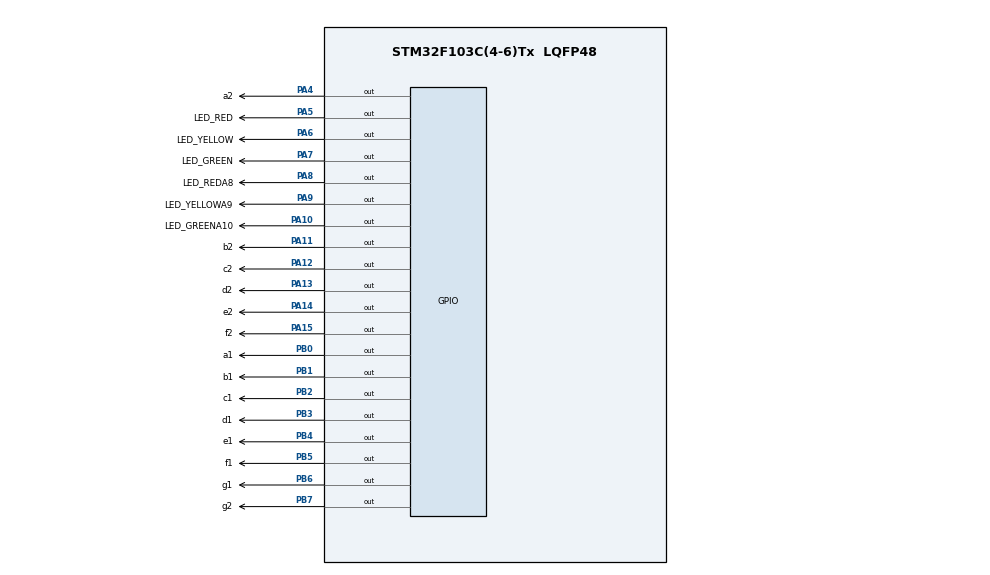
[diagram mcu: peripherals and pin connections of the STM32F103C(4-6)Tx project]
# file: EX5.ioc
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Mcu.Family=STM32F1
Mcu.Name=STM32F103C(4-6)Tx
Mcu.Package=LQFP48
NVIC.PriorityGroup=NVIC_PRIORITYGROUP_4
PA10.GPIO_Label=LED_GREENA10
PA10.Signal=GPIO_Output
PA11.GPIO_Label=b2
PA11.Signal=GPIO_Output
PA12.GPIO_Label=c2
PA12.Signal=GPIO_Output
PA13.GPIO_Label=d2
PA13.Signal=GPIO_Output
PA14.GPIO_Label=e2
PA14.Signal=GPIO_Output
PA15.GPIO_Label=f2
PA15.Signal=GPIO_Output
PA4.GPIO_Label=a2
PA4.Signal=GPIO_Output
PA5.GPIO_Label=LED_RED
PA5.Signal=GPIO_Output
PA6.GPIO_Label=LED_YELLOW
PA6.Signal=GPIO_Output
PA7.GPIO_Label=LED_GREEN
PA7.Signal=GPIO_Output
PA8.GPIO_Label=LED_REDA8
PA8.Signal=GPIO_Output
PA9.GPIO_Label=LED_YELLOWA9
PA9.Signal=GPIO_Output
PB0.GPIO_Label=a1
PB0.Signal=GPIO_Output
PB1.GPIO_Label=b1
PB1.Signal=GPIO_Output
PB2.GPIO_Label=c1
PB2.Signal=GPIO_Output
PB3.GPIO_Label=d1
PB3.Signal=GPIO_Output
PB4.GPIO_Label=e1
PB4.Signal=GPIO_Output
PB5.GPIO_Label=f1
PB5.Signal=GPIO_Output
PB6.GPIO_Label=g1
PB6.Signal=GPIO_Output
PB7.GPIO_Label=g2
PB7.Signal=GPIO_Output
ProjectManager.HeapSize=0x200
ProjectManager.StackSize=0x400
ProjectManager.TargetToolchain=STM32CubeIDE
RCC.APB1Freq_Value=8000000
RCC.APB2Freq_Value=8000000
VP_SYS_VS_ND.Mode=No_Debug
board=custom

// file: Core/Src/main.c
/* USER CODE BEGIN Header */
/**
  ******************************************************************************
  * @file           : main.c
  * @brief          : Main program body
  ******************************************************************************
  * @attention
  *
  * <h2><center>&copy; Copyright (c) 2022 STMicroelectronics.
  * All rights reserved.</center></h2>
  *
  * This software component is licensed by ST under BSD 3-Clause license,
  * the "License"; You may not use this file except in compliance with the
  * License. You may obtain a copy of the License at:
  *                        opensource.org/licenses/BSD-3-Clause
  *
  ******************************************************************************
  */
/* USER CODE END Header */
#include "main.h"

void SystemClock_Config(void);
static void MX_GPIO_Init(void);

/* USER CODE BEGIN 0 */
void clearAllClock();
void setNumberOnClock(int num);
void clearNumberOnClock(int num);

void clearAllClock()
{
	HAL_GPIO_WritePin(GPIOA, led0_Pin, GPIO_PIN_RESET);
	HAL_GPIO_WritePin(GPIOA, led1_Pin, GPIO_PIN_RESET);
	HAL_GPIO_WritePin(GPIOA, led2_Pin, GPIO_PIN_RESET);
	HAL_GPIO_WritePin(GPIOA, led3_Pin, GPIO_PIN_RESET);
	HAL_GPIO_WritePin(GPIOA, led4_Pin, GPIO_PIN_RESET);
	HAL_GPIO_WritePin(GPIOA, led5_Pin, GPIO_PIN_RESET);
	HAL_GPIO_WritePin(GPIOA, led6_Pin, GPIO_PIN_RESET);
	HAL_GPIO_WritePin(GPIOA, led7_Pin, GPIO_PIN_RESET);
	HAL_GPIO_WritePin(GPIOA, led8_Pin, GPIO_PIN_RESET);
	HAL_GPIO_WritePin(GPIOA, led9_Pin, GPIO_PIN_RESET);
	HAL_GPIO_WritePin(GPIOA, led10_Pin, GPIO_PIN_RESET);
	HAL_GPIO_WritePin(GPIOA, led11_Pin, GPIO_PIN_RESET);
}

void setNumberOnClock(int num)
{
	if(num == 0) HAL_GPIO_WritePin(led0_GPIO_Port, led0_Pin, GPIO_PIN_SET);
	if(num == 1) HAL_GPIO_WritePin(led1_GPIO_Port, led1_Pin, GPIO_PIN_SET);
	if(num == 2) HAL_GPIO_WritePin(led2_GPIO_Port, led2_Pin, GPIO_PIN_SET);
	if(num == 3) HAL_GPIO_WritePin(led3_GPIO_Port, led3_Pin, GPIO_PIN_SET);
	if(num == 4) HAL_GPIO_WritePin(led4_GPIO_Port, led4_Pin, GPIO_PIN_SET);
	if(num == 5) HAL_GPIO_WritePin(led5_GPIO_Port, led5_Pin, GPIO_PIN_SET);
	if(num == 6) HAL_GPIO_WritePin(led6_GPIO_Port, led6_Pin, GPIO_PIN_SET);
	if(num == 7) HAL_GPIO_WritePin(led7_GPIO_Port, led7_Pin, GPIO_PIN_SET);
	if(num == 8) HAL_GPIO_WritePin(led8_GPIO_Port, led8_Pin, GPIO_PIN_SET);
	if(num == 9) HAL_GPIO_WritePin(led9_GPIO_Port, led9_Pin, GPIO_PIN_SET);
	if(num == 10) HAL_GPIO_WritePin(led10_GPIO_Port, led10_Pin, GPIO_PIN_SET);
	if(num == 11) HAL_GPIO_WritePin(led11_GPIO_Port, led11_Pin, GPIO_PIN_SET);
}

void clearNumberOnClock(int num)
{
	if(num == 0) HAL_GPIO_WritePin(led0_GPIO_Port, led0_Pin, GPIO_PIN_RESET);
	if(num == 1) HAL_GPIO_WritePin(led1_GPIO_Port, led1_Pin, GPIO_PIN_RESET);
	if(num == 2) HAL_GPIO_WritePin(led2_GPIO_Port, led2_Pin, GPIO_PIN_RESET);
	if(num == 3) HAL_GPIO_WritePin(led3_GPIO_Port, led3_Pin, GPIO_PIN_RESET);
	if(num == 4) HAL_GPIO_WritePin(led4_GPIO_Port, led4_Pin, GPIO_PIN_RESET);
	if(num == 5) HAL_GPIO_WritePin(led5_GPIO_Port, led5_Pin, GPIO_PIN_RESET);
	if(num == 6) HAL_GPIO_WritePin(led6_GPIO_Port, led6_Pin, GPIO_PIN_RESET);
	if(num == 7) HAL_GPIO_WritePin(led7_GPIO_Port, led7_Pin, GPIO_PIN_RESET);
	if(num == 8) HAL_GPIO_WritePin(led8_GPIO_Port, led8_Pin, GPIO_PIN_RESET);
	if(num == 9) HAL_GPIO_WritePin(led9_GPIO_Port, led9_Pin, GPIO_PIN_RESET);
	if(num == 10) HAL_GPIO_WritePin(led10_GPIO_Port, led10_Pin, GPIO_PIN_RESET);
	if(num == 11) HAL_GPIO_WritePin(led11_GPIO_Port, led11_Pin, GPIO_PIN_RESET);
}
/* USER CODE END 0 */

int main(void)
{

  /* MCU Configuration--------------------------------------------------------*/

  /* Reset of all peripherals, Initializes the Flash interface and the Systick. */
  HAL_Init();

  /* Configure the system clock */
  SystemClock_Config();

  /* Initialize all configured peripherals */
  MX_GPIO_Init();

  /* Infinite loop */
  /* USER CODE BEGIN WHILE */

  // initial hour, minute, second
  int count_second = 0;
  int count_minute = 0;
  int count_hour = 0;

  while (1)
  {
    /* USER CODE END WHILE */

    /* USER CODE BEGIN 3 */

	  //---------- hien thuc kim giay-----------
	  if(count_second == 60)// kim giay chay du 5 vong
	  {
		  // kiem tra dieu kien kim gio, phut, giay trung nhau
		  if((count_second/5 - 1) != (count_minute/5) && (count_second/5 - 1) != count_hour)
		  {
			  //xoa kim giay, tao hieu ung chuyen dong
			  clearNumberOnClock(count_second/5 - 1);
		  }
		  count_minute ++;// cap nhat minute
		  count_second = 0;// reset second ve 0
	  }

	  // kiem tra dieu kien kim gio, phut, giay trung nhau
	  if((count_second/5 - 1) != (count_minute/5) && (count_second/5 - 1) != count_hour)
	  {
		  clearNumberOnClock(count_second/5 - 1);
	  }
	  // hien thi kim giay
	  setNumberOnClock(count_second/5);
	  count_second ++;

	  //--------- hien thuc kim phut----------
	  if(count_minute == 60)//kim phut chay du 1 vong
	  {
		  // kiem tra dieu kien kim gio, phut, giay trung nhau
		  if((count_minute/5 -1) != (count_second/5) && (count_minute/5 -1) != count_hour)
		  {
			  //xoa kim phut, tao hieu ung chuyen dong
			  clearNumberOnClock(count_minute/5 -1);
		  }
		  count_hour ++;// cap nhat kim gio
		  count_minute = 0;// reset kim phut ve 0
	  }

	  // kiem tra dieu kien kim gio, phut, giay trung nhau
	  if((count_minute/5 -1) != (count_second/5) && (count_minute/5 -1) != count_hour)
	  {
		  //xoa kim phut, tao hieu ung chuyen dong
		  clearNumberOnClock(count_minute/5 -1);
	  }
	  // hien thi kim phut
	  setNumberOnClock(count_minute/5);

	  // ------------hien thuc kim gio------------
	  if(count_hour == 12)// kim gio quay duoc 1 vong
	  {
		  // kiem tra dieu kien kim gio, phut, giay trung nhau
		  if((count_hour -1) != (count_minute/5) && (count_hour -1) != (count_second/5))
		  {
			  //xoa kim gio, tao hieu ung chuyen dong
			  clearNumberOnClock(count_hour -1);
		  }
		  count_hour = 0;// reset kim phut ve 0
	  }
	  // kiem tra dieu kien kim gio, phut, giay trung nhau
	  if((count_hour -1) != (count_minute/5) && (count_hour -1) != (count_second/5))
	  {
		  //xoa kim gio, tao hieu ung chuyen dong
		  clearNumberOnClock(count_hour -1);
	  }
	  // hien thi kim gio
	  setNumberOnClock(count_hour);

	  HAL_Delay(50);
  }
  /* USER CODE END 3 */
}

void SystemClock_Config(void)
{
  RCC_OscInitTypeDef RCC_OscInitStruct = {0};
  RCC_ClkInitTypeDef RCC_ClkInitStruct = {0};

  /** Initializes the RCC Oscillators according to the specified parameters
  * in the RCC_OscInitTypeDef structure.
  */
  RCC_OscInitStruct.OscillatorType = RCC_OSCILLATORTYPE_HSI;
  RCC_OscInitStruct.HSIState = RCC_HSI_ON;
  RCC_OscInitStruct.HSICalibrationValue = RCC_HSICALIBRATION_DEFAULT;
  RCC_OscInitStruct.PLL.PLLState = RCC_PLL_NONE;
  if (HAL_RCC_OscConfig(&RCC_OscInitStruct) != HAL_OK)
  {
    Error_Handler();
  }
  /** Initializes the CPU, AHB and APB buses clocks
  */
  RCC_ClkInitStruct.ClockType = RCC_CLOCKTYPE_HCLK|RCC_CLOCKTYPE_SYSCLK
                              |RCC_CLOCKTYPE_PCLK1|RCC_CLOCKTYPE_PCLK2;
  RCC_ClkInitStruct.SYSCLKSource = RCC_SYSCLKSOURCE_HSI;
  RCC_ClkInitStruct.AHBCLKDivider = RCC_SYSCLK_DIV1;
  RCC_ClkInitStruct.APB1CLKDivider = RCC_HCLK_DIV1;
  RCC_ClkInitStruct.APB2CLKDivider = RCC_HCLK_DIV1;

  if (HAL_RCC_ClockConfig(&RCC_ClkInitStruct, FLASH_LATENCY_0) != HAL_OK)
  {
    Error_Handler();
  }
}

static void MX_GPIO_Init(void)
{
  GPIO_InitTypeDef GPIO_InitStruct = {0};

  /* GPIO Ports Clock Enable */
  __HAL_RCC_GPIOA_CLK_ENABLE();

  /*Configure GPIO pin Output Level */
  HAL_GPIO_WritePin(GPIOA, led0_Pin|led1_Pin|led2_Pin|led3_Pin
                          |led4_Pin|led5_Pin|led6_Pin|led7_Pin
                          |led8_Pin|led9_Pin|led10_Pin|led11_Pin, GPIO_PIN_RESET);

  /*Configure GPIO pins : led0_Pin led1_Pin led2_Pin led3_Pin
                           led4_Pin led5_Pin led6_Pin led7_Pin
                           led8_Pin led9_Pin led10_Pin led11_Pin */
  GPIO_InitStruct.Pin = led0_Pin|led1_Pin|led2_Pin|led3_Pin
                          |led4_Pin|led5_Pin|led6_Pin|led7_Pin
                          |led8_Pin|led9_Pin|led10_Pin|led11_Pin;
  GPIO_InitStruct.Mode = GPIO_MODE_OUTPUT_PP;
  GPIO_InitStruct.Pull = GPIO_NOPULL;
  GPIO_InitStruct.Speed = GPIO_SPEED_FREQ_LOW;
  HAL_GPIO_Init(GPIOA, &GPIO_InitStruct);

}

void Error_Handler(void)
{
  __disable_irq();
  while (1)
  {
  }
}

/************************ (C) COPYRIGHT STMicroelectronics *****END OF FILE****/
